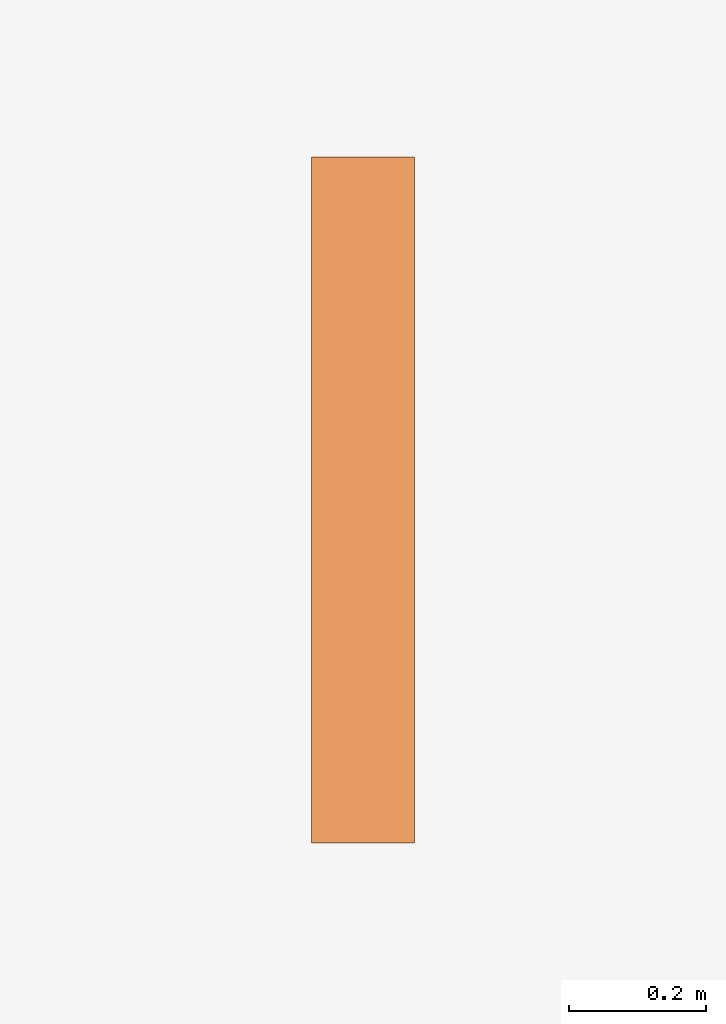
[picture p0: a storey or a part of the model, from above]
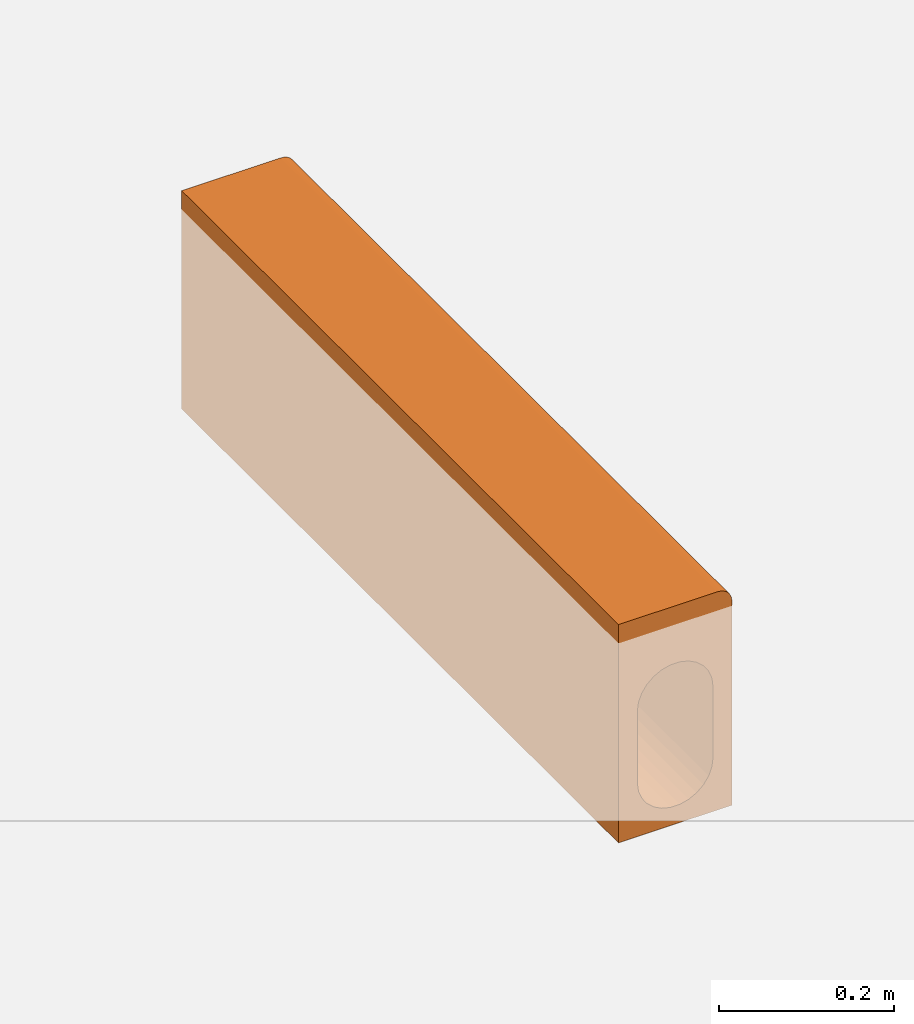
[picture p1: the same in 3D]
Properties of the parts of a building model (IFC2X3)

# File
Description: ViewDefinition [CoordinationView]
File name: 4236 - Centre Stone - 1000mm LG.ifc
Time: 2013-09-02T12:42:24
Written by: Autodesk Revit 2013
Made in: 20120221_2030(x64)

# IfcProject, Project Number
LongName: Project Name; Phase: Project Status

# IfcSite, Default
RefLatitude: 42, 21, 30, 344238; RefLongitude: -71, -3, -35, -194702; RefElevation: 0 mm

# IfcBuilding
Pset_BuildingCommon - NumberOfStoreys: 1
Other - Project Name: Project Name; Project Address: ## Street City, State Zip; Client Name: Owner; Project Number: Project Number; Project Status: Project Status; Project Issue Date: Issue Date

# IfcBuildingStorey, Level 1
LongName: Level 1; Elevation: 0 mm
Constraints - Elevation Base: 0; Elevation: 0 mm
Graphics - Symbol at End 2 Default: yes; Line Weight: 1; Symbol: M_Level Head - Circle: M_Level Head - Circle; Symbol at End 1 Default: no; Color: 0; Line Pattern: Center
Dimensions - Computation Height: 0 mm
Identity Data - Structural: no; Name: Level 1; Building Story: yes

# IfcBuildingElementProxy: 4236 - Centre Stone - 1000mm LG, Civil-Drainage-Channel-ACO-KerbDrain-HB405:4236 - Centre Stone - 1000mm LG:4236 - Centre Stone - 1000mm LG:312781
In: Level 1
Material: ACO Polymer Concrete.
Constraints - Level: Level: Level 1; Moves With Nearby Elements: no
Dimensions - Volume: 27818889 mm3; Void Depth: -280 mm; Circular Void Depth: 2000 mm; Void Width: 150 mm; Void Length: 1000 mm
Phasing - Phase Created: New Construction
Pset_BuildingElementProxyCommon - Reference: 4236 - Centre Stone - 1000mm LG
General - SerialNumber: 0.000000; TagNumber: 0.000000
Construction - HB405 - 1000: no; RH inlet/outlet end cap: no; RH drop kerb: no; HB405 500_blindunit: no; Access Unit: no; HB405 - 500: no; LH drop kerb: no; LH inlet/outlet end cap: no; Centre Stone: yes; Closing end cap: no
Other - Revision: 1; CreatedBy: www.aco.co.uk
Identity Data - Product Page URL: http://www.aco.co.uk/product_detail.php?id=3; Maintenance guidelines: http://www.aco.co.uk/download.php?id=120; Cost: 0; Product Code: 4236; Assembly Description: Rain Water Drainage; Model: ACO KerbDrain HB405; e-mail Technical: technical@aco.co.uk; OmniClass Number: 23.70.50.24; Fax: +44 (0)1462 815895; Address: ACO Business Park, Hitchin Road, Shefford, Bedfordshire, United Kingdom SG17 5TE; Product brochure: http://www.aco.co.uk/download.php?id=120; Installation guidelines: http://www.aco.co.uk/download.php?id=120; Assembly Code: D2040; Price: POA - contact ACO; Manufacturer: ACO Technologies plc - ACO Water Management Division; OmniClass Title: Rainwater Removal; Model Description: Combined kerb and drainage system; URL: www.aco.co.uk; Telephone: +44 (0)1462 816666; Type Comments: ACO KerbDrain HB405 half battered centre stone unit 1000mm long; e-mail Sales: customersupport@aco.co.uk
Materials and Finishes - Access Cover/Frame Material: N/A; End Cap Colour: N/A; Connection Pipe Material Colour: N/A; Connection Pipe Material: N/A; End Cap Material: N/A; Access Cover/Frame Colour: N/A; Access Cover/Frame Finish: N/A; Channel Colour: Grey; Channel Material: Vienite® Synthetic Resin Concrete
Green Building Properties - Access Cover/Frame Recyclable: N/A; End Cap Recyclable: N/A; End Cap Recycled Material Content: N/A; Channel Recycled Material Content: 20% minimum; Access Cover/Frame Recycled Material Content: N/A; Channel Recyclable: Fully recyclable
Data - Product Dimensions: 1000mm x 150mm x 305mm (LxWxH); Drainage Slot Intake area: N/A; ACO Hydraulic Design Software: http://www.acodesign.co.uk; Drainage Slot Width: N/A; Installation - Concrete Grade: Refer to brochure; Concrete Surround Volume - Load Class A 15 - D 400 - Concrete Pavement: N/A; Connection Pipe O.D: N/A; Product Standard: BS EN 1433:2002, CE marked, Kitemarked; Load Class: A 15 - D 400; Hydraulic Performance: http://www.aco.co.uk/download.php?id=120; Concrete Surround Volume - Load Class A 15 - D 400 - Grass or Asphalt Pavement: N/A; Product Weight: 50.1 Kg; Invert Depth: 280mm; Channel C.S.A: 0.02mm²

# IfcOpeningElement: Recess (2)
In: Level 1
Constraints - Related to Mass: no; Level: Level: Level 1; Height Offset From Level: 0 mm; Room Bounding: yes
Dimensions - Thickness: 400 mm; Area: 151470000 mm2; Perimeter: 51360 mm; Volume: 60546000000 mm3
Phasing - Phase Created: New Construction
Structural - Enable Analytical Model: no; Structural: no
Analytical Properties - Roughness: 1; Absorptance: 0.1
Construction - Function: 0; Default Thickness: 400 mm
Materials and Finishes - Structural Material: Plant
Graphics - Coarse Scale Fill Color: 0

# IfcSlab: Floor:Generic Floor - 400mm, Floor:Generic Floor - 400mm:193825
In: Level 1
PredefinedType: FLOOR; Material: Plant 400 mm
Constraints - Related to Mass: no; Level: Level: Level 1; Height Offset From Level: 0 mm; Room Bounding: yes
Dimensions - Thickness: 400 mm; Area: 151470000 mm2; Perimeter: 51360 mm; Volume: 60546000000 mm3
Phasing - Phase Created: New Construction
Structural - Enable Analytical Model: no; Structural: no
Pset_SlabCommon - Reference: Generic Floor - 400mm; IsExternal: no; LoadBearing: yes
Analytical Properties - Roughness: 1; Absorptance: 0.1
Construction - Function: 0; Default Thickness: 400 mm
Materials and Finishes - Structural Material: Plant
Graphics - Coarse Scale Fill Color: 0
